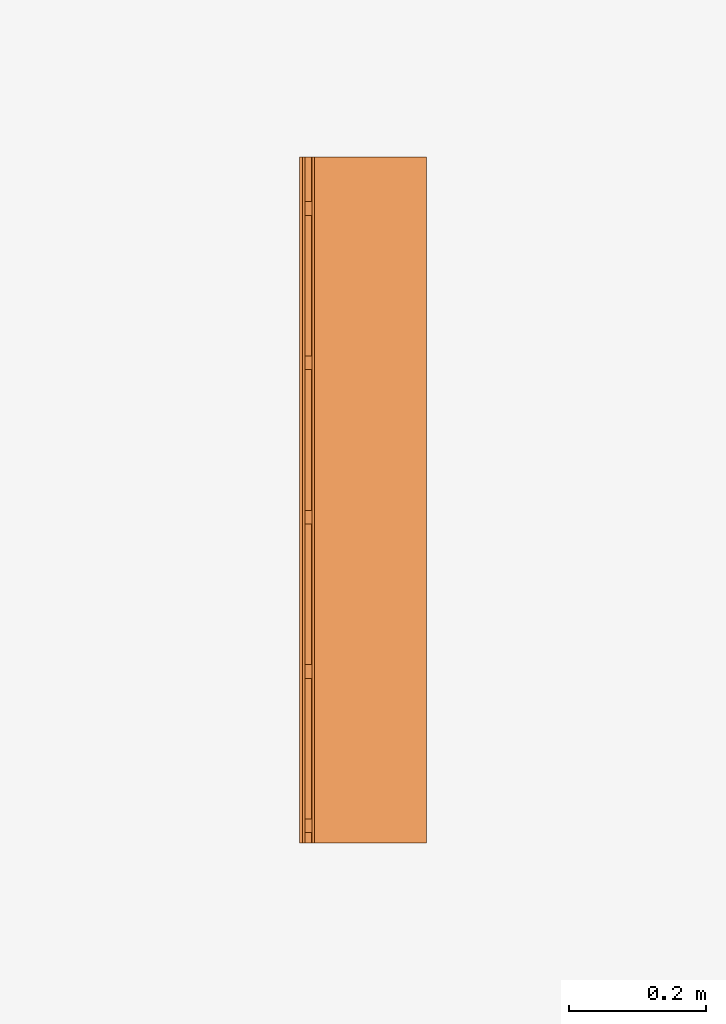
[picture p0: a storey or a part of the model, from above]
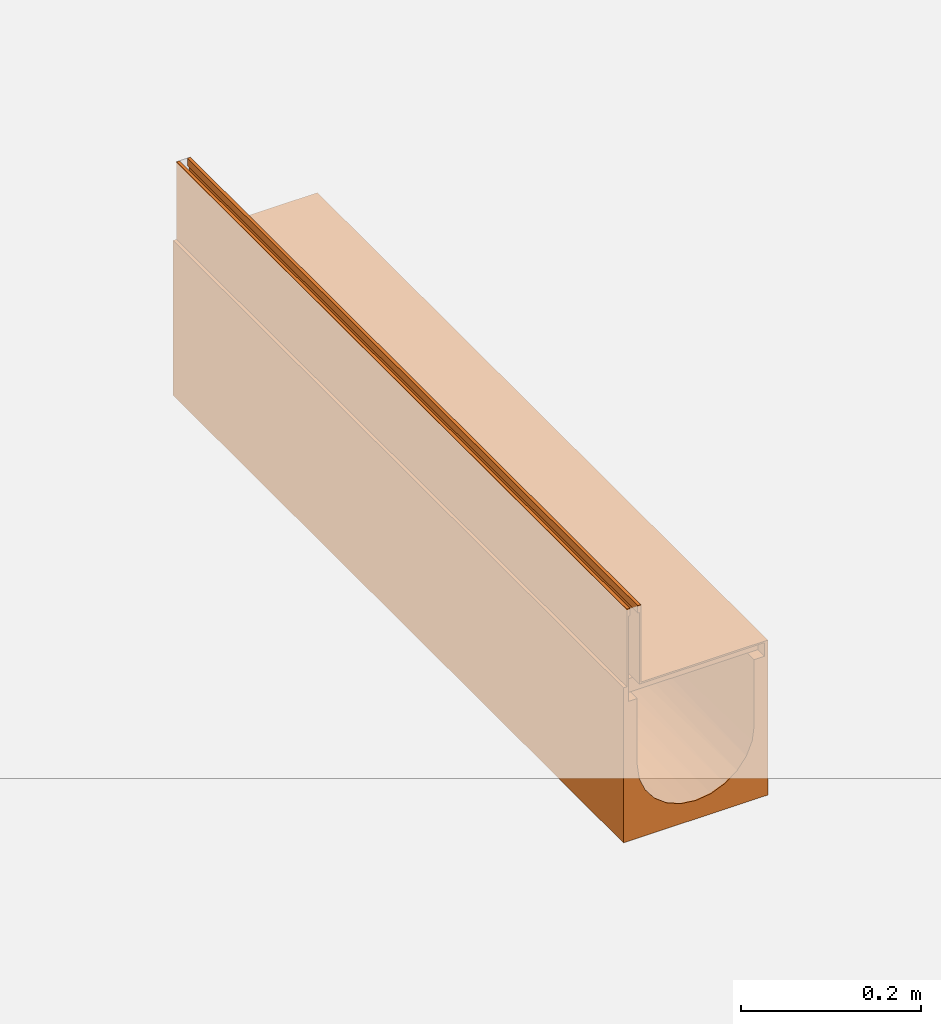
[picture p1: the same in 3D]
Properties of the parts of a building model (IFC2X3)

# File
Description: ViewDefinition [CoordinationView]
File name: 23150 - No 0.0 Constant Depth Channel - 1000mm LG - Invert Depth 185mm.ifc
Time: 2013-10-30T12:20:21
Written by: Autodesk Revit 2013
Made in: 20120221_2030(x64)

# IfcProject, Project Number
LongName: Project Name; Phase: Project Status

# IfcSite, Default
RefLatitude: 42, 21, 30, 344238; RefLongitude: -71, -3, -35, -194702; RefElevation: 0 mm

# IfcBuilding
Pset_BuildingCommon - NumberOfStoreys: 1
Other - Project Name: Project Name; Client Name: Owner; Project Issue Date: Issue Date; Project Number: Project Number; Project Address: ## Street City, State Zip; Project Status: Project Status

# IfcBuildingStorey, Level 1
LongName: Level 1; Elevation: 0 mm
Constraints - Elevation Base: 0; Elevation: 0 mm
Graphics - Line Pattern: Center; Symbol at End 1 Default: no; Line Weight: 1; Color: 0; Symbol at End 2 Default: yes; Symbol: M_Level Head - Circle: M_Level Head - Circle
Identity Data - Name: Level 1; Building Story: yes; Structural: no
Dimensions - Computation Height: 0 mm

# IfcBuildingElementProxy: 23150 - No 0.0 Constant Depth Channel - 1000mm LG - Invert Depth 185mm, Civil-Drainage-Channel-ACO-MultiDrain-M150D-Brickslot-Channel-System:23150 - No 0.0 Constant Depth Channel - 1000mm LG - Invert Depth 185mm:23150 - No 0.0 Constant Depth Channel - 1000mm LG - Invert Depth 185mm:196059
In: Level 1
Material: Steel, Galvanized, Vienite® Synthetic Resin Concrete
Dimensions - Length: 1000 mm; Volume: 13712793 mm3; Custom_Void_Length: 0 mm; Brickslot Access Unit Void Depth: -6000 mm; Brickslot Access Unit Void Bottom Depth: -6105 mm; Brickslot Void Length: -1000 mm; Brickslot Grating Void Depth: 0 mm; EndCap Position: 1000 mm; FloorCut_Length: -1000 mm; FloorCut_Depth: 210 mm; FloorCut_HorPosition: 92.5 mm; InvDepth: 110 mm; Floor Cut Gap: 105 mm; FloorCut_Width: 185 mm; EndCap_Height: -210 mm; End Cap Thickess: 3 mm; Depth: 210 mm; Length Drain: -1000 mm; Floor cut gap depth for access unit: 105 mm
Phasing - Phase Created: New Construction
Construction - 23176_Load Class C250 & D400_Brickslot Grating_Galvanized Steel_500mm Long: no; 23159_Universal Endcap (Female End): no; 23159_Universal Endcap (Male End): no; 23177_Load Class C250 & D400_Brickslot_Access Unit_Galvanized Steel_500mm Long: no; 23175_Load Class C250 & D400_Brickslot Grating_Galvanized Steel_1000mm Long: yes; Constant Depth Channel_1000: yes; Constant Depth Channel_500: no; 23157_Shallow Depth Channel with seal: no; 23156_Shallow Depth Channel: no; Sump Unit: no
Constraints - Moves With Nearby Elements: no; Level: Level: Level 1
Pset_BuildingElementProxyCommon - Reference: 23150 - No 0.0 Constant Depth Channel - 1000mm LG - Invert Depth 185mm
Data - Concrete Surround Volume - Load Class B 125 - C 250 - Concrete Pavement: 0.14m³/m; Product Weight: 21.6 Kg; Concrete Surround Volume - Load Class A 15 - Concrete Pavement: 0.09m³/m; Product Standard: BS EN 1433:2002, CE marked; Pre-formed Outlet Ø: N/A; Hydraulic Performance: http://www.aco.co.uk/download.php?id=173; Product Dimensions: 1000mm x 185mm x 210mm (LxWxH); ACO Hydraulic Design Software: http://www.acodesign.co.uk; Concrete Surround Volume - Load Class D 400 - Concrete Pavement: 0.21m³/m; Invert Depth: 185mm; Load Class: A 15 - D 400; Installation - Concrete Grade: Refer to brochure; Channel C.S.A: 0.020m²
General - SerialNumber: 0; TagNumber: 0
Materials and Finishes - Edge Rail Finish: Pre-galvanised; Channel Material: Vienite® Synthetic Resin Concrete; Edge Rail Colour: Silver; Channel Colour: Brown; Edge Rail Material: Steel
Identity Data - OmniClass Number: 23.70.50.24; Address: ACO Business Park, Hitchin Road, Shefford, Bedfordshire, United Kingdom SG17 5TE; Cost: 0; Installation guidelines: http://www.aco.co.uk/download.php?id=173; OmniClass Title: Rainwater Removal; Watermark 2: This file is water marked and users are prohibited to reproduce, adapt, distribute this information; Model Description: Channel drainage system; Assembly Code: D2040; Fax: +44 (0)1462 815895; Price: POA - contact ACO; e-mail Sales: customersupport@aco.co.uk; e-mail Technical: technical@aco.co.uk; URL: www.aco.co.uk; Product brochure: http://www.aco.co.uk/download.php?id=173; Watermarked By: www.aco.co.uk; Product Page URL: http://www.aco.co.uk/product_detail.php?id=58; Assembly Description: Rain Water Drainage; Watermarked With: BIM Manager Premium Suite; Model: ACO MultiDrain MD Brickslot - M150D; Telephone: +44 (0)1462 816666; Type Comments: ACO MultiDrain M150D 0.0 Constant Depth Channel 1000mm Long; Product Code: 23150; Watermark 1: This file is the property of ACO Technologies PLC; Maintenance guidelines: http://www.aco.co.uk/download.php?id=173; Manufacturer: ACO Technologies plc - ACO Water Management Division
Green Building Properties - Channel Recyclable: Fully recyclable; Edge Rail Recycled Material Content: Between 40% - 90%; Edge Rail Recyclable: Fully recyclable; Channel Recycled Material Content: 20% minimum
Other - Revision: 1; CreatedBy: www.aco.co.uk
Model Properties - Brickslot Access Unit Product code 23177: Load Class C250/D400 - Brickslot Access Unit Galvanised steel - 500mm long x 105mm high - 10mm Slot -Intake area 10000mm²/m - 7.0kg; End Cap Product code 23159: No. 306 Universal End Cap - 185mm wide x 310mm long - Spigot Ø110mm x 50mm long - Silver - Co-Polymer Polypropylene - 0.3kg; Brickslot Grating Product code 23175: Load Class C250/D400 - Brickslot Galvanized Steel - 1000mm long x 105mm high - 10mm Slot - Intake area 10000mm²/m - 7.6kg; Brickslot Grating Product code 23176: Load Class C250/D400 -Brickslot Galvanized Steel - 500mm long x 105mm high - 10mm Slot - Intake area 10000mm²/m - 3.8kg

# IfcOpeningElement: Recess (2)
In: Level 1
Constraints - Room Bounding: yes; Level: Level: Level 1; Height Offset From Level: 0 mm; Related to Mass: no
Dimensions - Thickness: 400 mm; Area: 25000000 mm2; Perimeter: 20000 mm; Volume: 9959260000 mm3
Structural - Enable Analytical Model: no; Structural: no
Phasing - Phase Created: New Construction
Construction - Default Thickness: 400 mm; Function: 0
Analytical Properties - Heat Transfer Coefficient (U): 2.0925; Thermal Resistance (R): 0.477897; Roughness: 1; Absorptance: 0.1; Thermal mass: 543920
Graphics - Coarse Scale Fill Color: 0
Materials and Finishes - Structural Material: Earth

# IfcSlab: Floor:Generic Floor - 400mm, Floor:Generic Floor - 400mm:193825
In: Level 1
PredefinedType: FLOOR; Material: Earth 400 mm
Constraints - Room Bounding: yes; Level: Level: Level 1; Height Offset From Level: 0 mm; Related to Mass: no
Dimensions - Thickness: 400 mm; Area: 25000000 mm2; Perimeter: 20000 mm; Volume: 9959260000 mm3
Structural - Enable Analytical Model: no; Structural: no
Phasing - Phase Created: New Construction
Pset_SlabCommon - Reference: Generic Floor - 400mm; IsExternal: no; LoadBearing: yes
Construction - Default Thickness: 400 mm; Function: 0
Analytical Properties - Heat Transfer Coefficient (U): 2.0925; Thermal Resistance (R): 0.477897; Roughness: 1; Absorptance: 0.1; Thermal mass: 543920
Graphics - Coarse Scale Fill Color: 0
Materials and Finishes - Structural Material: Earth
